VERSION 5.7 ;
  NOWIREEXTENSIONATPIN ON ;
  DIVIDERCHAR "/" ;
  BUSBITCHARS "[]" ;
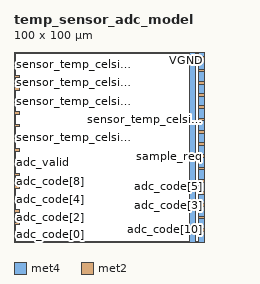
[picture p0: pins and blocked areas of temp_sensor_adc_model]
MACRO temp_sensor_adc_model
  CLASS BLOCK ;
  FOREIGN temp_sensor_adc_model ;
  ORIGIN 0.000 0.000 ;
  SIZE 100.000 BY 100.000 ;
  PIN VGND
    DIRECTION INOUT ;
    USE GROUND ;
      SHAPE ABUTMENT ;
    PORT
      LAYER met4 ;
        RECT 97.000 0.000 100.000 100.000 ;
    END
  END VGND
  PIN VPWR
    DIRECTION INOUT ;
    USE POWER ;
      SHAPE ABUTMENT ;
    PORT
      LAYER met4 ;
        RECT 92.500 0.000 95.500 100.000 ;
    END
  END VPWR
  PIN adc_code[0]
    DIRECTION OUTPUT ;
    USE SIGNAL ;
    PORT
      LAYER met2 ;
        RECT 0.000 2.500 3.000 3.950 ;
    END
  END adc_code[0]
  PIN adc_code[10]
    DIRECTION OUTPUT ;
    USE SIGNAL ;
    PORT
      LAYER met2 ;
        RECT 97.000 5.725 100.000 7.175 ;
    END
  END adc_code[10]
  PIN adc_code[11]
    DIRECTION OUTPUT ;
    USE SIGNAL ;
    PORT
      LAYER met2 ;
        RECT 0.000 8.950 3.000 10.405 ;
    END
  END adc_code[11]
  PIN adc_code[1]
    DIRECTION OUTPUT ;
    USE SIGNAL ;
    PORT
      LAYER met2 ;
        RECT 97.000 12.175 100.000 13.630 ;
    END
  END adc_code[1]
  PIN adc_code[2]
    DIRECTION OUTPUT ;
    USE SIGNAL ;
    PORT
      LAYER met2 ;
        RECT 0.000 15.405 3.000 16.855 ;
    END
  END adc_code[2]
  PIN adc_code[3]
    DIRECTION OUTPUT ;
    USE SIGNAL ;
    PORT
      LAYER met2 ;
        RECT 97.000 18.630 100.000 20.080 ;
    END
  END adc_code[3]
  PIN adc_code[4]
    DIRECTION OUTPUT ;
    USE SIGNAL ;
    PORT
      LAYER met2 ;
        RECT 0.000 21.855 3.000 23.305 ;
    END
  END adc_code[4]
  PIN adc_code[5]
    DIRECTION OUTPUT ;
    USE SIGNAL ;
    PORT
      LAYER met2 ;
        RECT 97.000 25.080 100.000 26.530 ;
    END
  END adc_code[5]
  PIN adc_code[6]
    DIRECTION OUTPUT ;
    USE SIGNAL ;
    PORT
      LAYER met2 ;
        RECT 0.000 28.305 3.000 29.760 ;
    END
  END adc_code[6]
  PIN adc_code[7]
    DIRECTION OUTPUT ;
    USE SIGNAL ;
    PORT
      LAYER met2 ;
        RECT 97.000 31.530 100.000 32.985 ;
    END
  END adc_code[7]
  PIN adc_code[8]
    DIRECTION OUTPUT ;
    USE SIGNAL ;
    PORT
      LAYER met2 ;
        RECT 0.000 34.760 3.000 36.210 ;
    END
  END adc_code[8]
  PIN adc_code[9]
    DIRECTION OUTPUT ;
    USE SIGNAL ;
    PORT
      LAYER met2 ;
        RECT 97.000 37.985 100.000 39.435 ;
    END
  END adc_code[9]
  PIN adc_valid
    DIRECTION OUTPUT ;
    USE SIGNAL ;
    PORT
      LAYER met2 ;
        RECT 0.000 41.210 3.000 42.660 ;
    END
  END adc_valid
  PIN avdd
    DIRECTION INOUT ;
    USE POWER ;
      SHAPE ABUTMENT ;
    PORT
      LAYER met4 ;
        RECT 92.500 0.000 95.500 100.000 ;
    END
  END avdd
  PIN avss
    DIRECTION INOUT ;
    USE GROUND ;
      SHAPE ABUTMENT ;
    PORT
      LAYER met4 ;
        RECT 97.000 0.000 100.000 100.000 ;
    END
  END avss
  PIN sample_req
    DIRECTION INPUT ;
    USE SIGNAL ;
    PORT
      LAYER met2 ;
        RECT 97.000 44.435 100.000 45.885 ;
    END
  END sample_req
  PIN sensor_temp_celsius[0]
    DIRECTION INPUT ;
    USE SIGNAL ;
    PORT
      LAYER met2 ;
        RECT 0.000 47.660 3.000 49.115 ;
    END
  END sensor_temp_celsius[0]
  PIN sensor_temp_celsius[10]
    DIRECTION INPUT ;
    USE SIGNAL ;
    PORT
      LAYER met2 ;
        RECT 97.000 50.885 100.000 52.340 ;
    END
  END sensor_temp_celsius[10]
  PIN sensor_temp_celsius[11]
    DIRECTION INPUT ;
    USE SIGNAL ;
    PORT
      LAYER met2 ;
        RECT 0.000 54.115 3.000 55.565 ;
    END
  END sensor_temp_celsius[11]
  PIN sensor_temp_celsius[12]
    DIRECTION INPUT ;
    USE SIGNAL ;
    PORT
      LAYER met2 ;
        RECT 97.000 57.340 100.000 58.790 ;
    END
  END sensor_temp_celsius[12]
  PIN sensor_temp_celsius[13]
    DIRECTION INPUT ;
    USE SIGNAL ;
    PORT
      LAYER met2 ;
        RECT 0.000 60.565 3.000 62.015 ;
    END
  END sensor_temp_celsius[13]
  PIN sensor_temp_celsius[14]
    DIRECTION INPUT ;
    USE SIGNAL ;
    PORT
      LAYER met2 ;
        RECT 97.000 63.790 100.000 65.240 ;
    END
  END sensor_temp_celsius[14]
  PIN sensor_temp_celsius[15]
    DIRECTION INPUT ;
    USE SIGNAL ;
    PORT
      LAYER met2 ;
        RECT 0.000 67.015 3.000 68.470 ;
    END
  END sensor_temp_celsius[15]
  PIN sensor_temp_celsius[1]
    DIRECTION INPUT ;
    USE SIGNAL ;
    PORT
      LAYER met2 ;
        RECT 97.000 70.240 100.000 71.695 ;
    END
  END sensor_temp_celsius[1]
  PIN sensor_temp_celsius[2]
    DIRECTION INPUT ;
    USE SIGNAL ;
    PORT
      LAYER met2 ;
        RECT 0.000 73.470 3.000 74.920 ;
    END
  END sensor_temp_celsius[2]
  PIN sensor_temp_celsius[3]
    DIRECTION INPUT ;
    USE SIGNAL ;
    PORT
      LAYER met2 ;
        RECT 97.000 76.695 100.000 78.145 ;
    END
  END sensor_temp_celsius[3]
  PIN sensor_temp_celsius[4]
    DIRECTION INPUT ;
    USE SIGNAL ;
    PORT
      LAYER met2 ;
        RECT 0.000 79.920 3.000 81.370 ;
    END
  END sensor_temp_celsius[4]
  PIN sensor_temp_celsius[5]
    DIRECTION INPUT ;
    USE SIGNAL ;
    PORT
      LAYER met2 ;
        RECT 97.000 83.145 100.000 84.595 ;
    END
  END sensor_temp_celsius[5]
  PIN sensor_temp_celsius[6]
    DIRECTION INPUT ;
    USE SIGNAL ;
    PORT
      LAYER met2 ;
        RECT 0.000 86.370 3.000 87.825 ;
    END
  END sensor_temp_celsius[6]
  PIN sensor_temp_celsius[7]
    DIRECTION INPUT ;
    USE SIGNAL ;
    PORT
      LAYER met2 ;
        RECT 97.000 89.595 100.000 91.050 ;
    END
  END sensor_temp_celsius[7]
  PIN sensor_temp_celsius[8]
    DIRECTION INPUT ;
    USE SIGNAL ;
    PORT
      LAYER met2 ;
        RECT 0.000 92.825 3.000 94.275 ;
    END
  END sensor_temp_celsius[8]
  PIN sensor_temp_celsius[9]
    DIRECTION INPUT ;
    USE SIGNAL ;
    PORT
      LAYER met2 ;
        RECT 97.000 96.050 100.000 97.500 ;
    END
  END sensor_temp_celsius[9]
END temp_sensor_adc_model
END LIBRARY
